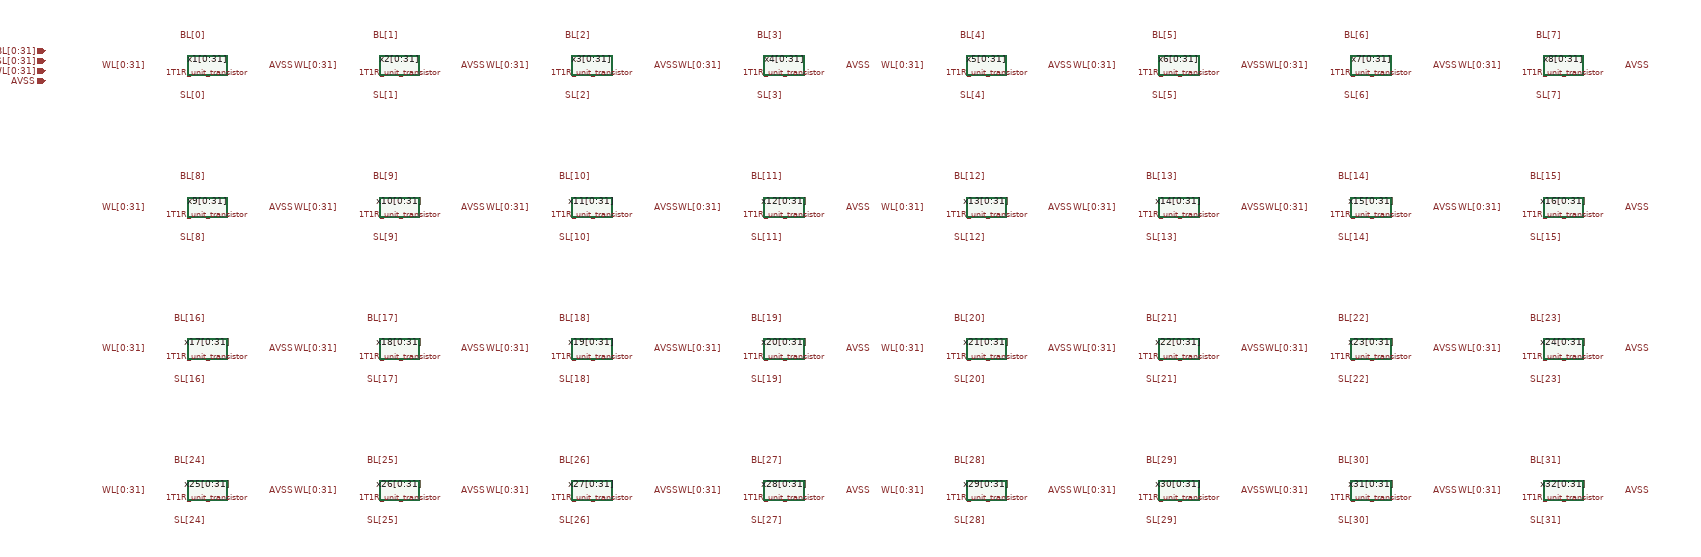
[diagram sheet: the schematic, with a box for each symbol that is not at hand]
v {xschem version=3.1.0 file_version=1.2
}
G {}
K {}
V {}
S {}
E {}
C {devices/iopin.sym} 0 -30 0 0 {name=p1 lab=BL[0:31]}
C {devices/iopin.sym} 0 -10 0 0 {name=p2 lab=SL[0:31]}
C {devices/ipin.sym} 0 10 0 0 {name=p3 lab=WL[0:31]}
C {devices/ipin.sym} 0 30 0 0 {name=p4 lab=AVSS}
C {Top_Level_Array/1T1R_unit_transistor.sym} 320 0 0 0 {name=x1[0:31]}
C {devices/lab_pin.sym} 200 0 0 0 {name=p5 sig_type=std_logic lab=WL[0:31]}
C {devices/lab_pin.sym} 440 0 0 1 {name=p6 sig_type=std_logic lab=AVSS}
C {devices/lab_pin.sym} 320 -60 3 1 {name=p7 sig_type=std_logic lab=BL[0]}
C {devices/lab_pin.sym} 320 60 1 1 {name=p8 sig_type=std_logic lab=SL[0]}
C {Top_Level_Array/1T1R_unit_transistor.sym} 700 0 0 0 {name=x2[0:31]}
C {devices/lab_pin.sym} 580 0 0 0 {name=p9 sig_type=std_logic lab=WL[0:31]}
C {devices/lab_pin.sym} 820 0 0 1 {name=p10 sig_type=std_logic lab=AVSS}
C {devices/lab_pin.sym} 700 -60 3 1 {name=p11 sig_type=std_logic lab=BL[1]}
C {devices/lab_pin.sym} 700 60 1 1 {name=p12 sig_type=std_logic lab=SL[1]}
C {Top_Level_Array/1T1R_unit_transistor.sym} 1080 0 0 0 {name=x3[0:31]}
C {devices/lab_pin.sym} 960 0 0 0 {name=p13 sig_type=std_logic lab=WL[0:31]}
C {devices/lab_pin.sym} 1200 0 0 1 {name=p14 sig_type=std_logic lab=AVSS}
C {devices/lab_pin.sym} 1080 -60 3 1 {name=p15 sig_type=std_logic lab=BL[2]}
C {devices/lab_pin.sym} 1080 60 1 1 {name=p16 sig_type=std_logic lab=SL[2]}
C {Top_Level_Array/1T1R_unit_transistor.sym} 1460 0 0 0 {name=x4[0:31]}
C {devices/lab_pin.sym} 1340 0 0 0 {name=p17 sig_type=std_logic lab=WL[0:31]}
C {devices/lab_pin.sym} 1580 0 0 1 {name=p18 sig_type=std_logic lab=AVSS}
C {devices/lab_pin.sym} 1460 -60 3 1 {name=p19 sig_type=std_logic lab=BL[3]}
C {devices/lab_pin.sym} 1460 60 1 1 {name=p20 sig_type=std_logic lab=SL[3]}
C {Top_Level_Array/1T1R_unit_transistor.sym} 1860 0 0 0 {name=x5[0:31]}
C {devices/lab_pin.sym} 1740 0 0 0 {name=p21 sig_type=std_logic lab=WL[0:31]}
C {devices/lab_pin.sym} 1980 0 0 1 {name=p22 sig_type=std_logic lab=AVSS}
C {devices/lab_pin.sym} 1860 -60 3 1 {name=p23 sig_type=std_logic lab=BL[4]}
C {devices/lab_pin.sym} 1860 60 1 1 {name=p24 sig_type=std_logic lab=SL[4]}
C {Top_Level_Array/1T1R_unit_transistor.sym} 2240 0 0 0 {name=x6[0:31]}
C {devices/lab_pin.sym} 2120 0 0 0 {name=p25 sig_type=std_logic lab=WL[0:31]}
C {devices/lab_pin.sym} 2360 0 0 1 {name=p26 sig_type=std_logic lab=AVSS}
C {devices/lab_pin.sym} 2240 -60 3 1 {name=p27 sig_type=std_logic lab=BL[5]}
C {devices/lab_pin.sym} 2240 60 1 1 {name=p28 sig_type=std_logic lab=SL[5]}
C {Top_Level_Array/1T1R_unit_transistor.sym} 2620 0 0 0 {name=x7[0:31]}
C {devices/lab_pin.sym} 2500 0 0 0 {name=p29 sig_type=std_logic lab=WL[0:31]}
C {devices/lab_pin.sym} 2740 0 0 1 {name=p30 sig_type=std_logic lab=AVSS}
C {devices/lab_pin.sym} 2620 -60 3 1 {name=p31 sig_type=std_logic lab=BL[6]}
C {devices/lab_pin.sym} 2620 60 1 1 {name=p32 sig_type=std_logic lab=SL[6]}
C {Top_Level_Array/1T1R_unit_transistor.sym} 3000 0 0 0 {name=x8[0:31]}
C {devices/lab_pin.sym} 2880 0 0 0 {name=p33 sig_type=std_logic lab=WL[0:31]}
C {devices/lab_pin.sym} 3120 0 0 1 {name=p34 sig_type=std_logic lab=AVSS}
C {devices/lab_pin.sym} 3000 -60 3 1 {name=p35 sig_type=std_logic lab=BL[7]}
C {devices/lab_pin.sym} 3000 60 1 1 {name=p36 sig_type=std_logic lab=SL[7]}
C {Top_Level_Array/1T1R_unit_transistor.sym} 320 280 0 0 {name=x9[0:31]}
C {devices/lab_pin.sym} 200 280 0 0 {name=p37 sig_type=std_logic lab=WL[0:31]}
C {devices/lab_pin.sym} 440 280 0 1 {name=p38 sig_type=std_logic lab=AVSS}
C {devices/lab_pin.sym} 320 220 3 1 {name=p39 sig_type=std_logic lab=BL[8]}
C {devices/lab_pin.sym} 320 340 1 1 {name=p40 sig_type=std_logic lab=SL[8]}
C {Top_Level_Array/1T1R_unit_transistor.sym} 700 280 0 0 {name=x10[0:31]}
C {devices/lab_pin.sym} 580 280 0 0 {name=p41 sig_type=std_logic lab=WL[0:31]}
C {devices/lab_pin.sym} 820 280 0 1 {name=p42 sig_type=std_logic lab=AVSS}
C {devices/lab_pin.sym} 700 220 3 1 {name=p43 sig_type=std_logic lab=BL[9]}
C {devices/lab_pin.sym} 700 340 1 1 {name=p44 sig_type=std_logic lab=SL[9]}
C {Top_Level_Array/1T1R_unit_transistor.sym} 1080 280 0 0 {name=x11[0:31]}
C {devices/lab_pin.sym} 960 280 0 0 {name=p45 sig_type=std_logic lab=WL[0:31]}
C {devices/lab_pin.sym} 1200 280 0 1 {name=p46 sig_type=std_logic lab=AVSS}
C {devices/lab_pin.sym} 1080 220 3 1 {name=p47 sig_type=std_logic lab=BL[10]}
C {devices/lab_pin.sym} 1080 340 1 1 {name=p48 sig_type=std_logic lab=SL[10]}
C {Top_Level_Array/1T1R_unit_transistor.sym} 1460 280 0 0 {name=x12[0:31]}
C {devices/lab_pin.sym} 1340 280 0 0 {name=p49 sig_type=std_logic lab=WL[0:31]}
C {devices/lab_pin.sym} 1580 280 0 1 {name=p50 sig_type=std_logic lab=AVSS}
C {devices/lab_pin.sym} 1460 220 3 1 {name=p51 sig_type=std_logic lab=BL[11]}
C {devices/lab_pin.sym} 1460 340 1 1 {name=p52 sig_type=std_logic lab=SL[11]}
C {Top_Level_Array/1T1R_unit_transistor.sym} 1860 280 0 0 {name=x13[0:31]}
C {devices/lab_pin.sym} 1740 280 0 0 {name=p53 sig_type=std_logic lab=WL[0:31]}
C {devices/lab_pin.sym} 1980 280 0 1 {name=p54 sig_type=std_logic lab=AVSS}
C {devices/lab_pin.sym} 1860 220 3 1 {name=p55 sig_type=std_logic lab=BL[12]}
C {devices/lab_pin.sym} 1860 340 1 1 {name=p56 sig_type=std_logic lab=SL[12]}
C {Top_Level_Array/1T1R_unit_transistor.sym} 2240 280 0 0 {name=x14[0:31]}
C {devices/lab_pin.sym} 2120 280 0 0 {name=p57 sig_type=std_logic lab=WL[0:31]}
C {devices/lab_pin.sym} 2360 280 0 1 {name=p58 sig_type=std_logic lab=AVSS}
C {devices/lab_pin.sym} 2240 220 3 1 {name=p59 sig_type=std_logic lab=BL[13]}
C {devices/lab_pin.sym} 2240 340 1 1 {name=p60 sig_type=std_logic lab=SL[13]}
C {Top_Level_Array/1T1R_unit_transistor.sym} 2620 280 0 0 {name=x15[0:31]}
C {devices/lab_pin.sym} 2500 280 0 0 {name=p61 sig_type=std_logic lab=WL[0:31]}
C {devices/lab_pin.sym} 2740 280 0 1 {name=p62 sig_type=std_logic lab=AVSS}
C {devices/lab_pin.sym} 2620 220 3 1 {name=p63 sig_type=std_logic lab=BL[14]}
C {devices/lab_pin.sym} 2620 340 1 1 {name=p64 sig_type=std_logic lab=SL[14]}
C {Top_Level_Array/1T1R_unit_transistor.sym} 3000 280 0 0 {name=x16[0:31]}
C {devices/lab_pin.sym} 2880 280 0 0 {name=p65 sig_type=std_logic lab=WL[0:31]}
C {devices/lab_pin.sym} 3120 280 0 1 {name=p66 sig_type=std_logic lab=AVSS}
C {devices/lab_pin.sym} 3000 220 3 1 {name=p67 sig_type=std_logic lab=BL[15]}
C {devices/lab_pin.sym} 3000 340 1 1 {name=p68 sig_type=std_logic lab=SL[15]}
C {Top_Level_Array/1T1R_unit_transistor.sym} 320 560 0 0 {name=x17[0:31]}
C {devices/lab_pin.sym} 200 560 0 0 {name=p69 sig_type=std_logic lab=WL[0:31]}
C {devices/lab_pin.sym} 440 560 0 1 {name=p70 sig_type=std_logic lab=AVSS}
C {devices/lab_pin.sym} 320 500 3 1 {name=p71 sig_type=std_logic lab=BL[16]}
C {devices/lab_pin.sym} 320 620 1 1 {name=p72 sig_type=std_logic lab=SL[16]}
C {Top_Level_Array/1T1R_unit_transistor.sym} 700 560 0 0 {name=x18[0:31]}
C {devices/lab_pin.sym} 580 560 0 0 {name=p73 sig_type=std_logic lab=WL[0:31]}
C {devices/lab_pin.sym} 820 560 0 1 {name=p74 sig_type=std_logic lab=AVSS}
C {devices/lab_pin.sym} 700 500 3 1 {name=p75 sig_type=std_logic lab=BL[17]}
C {devices/lab_pin.sym} 700 620 1 1 {name=p76 sig_type=std_logic lab=SL[17]}
C {Top_Level_Array/1T1R_unit_transistor.sym} 1080 560 0 0 {name=x19[0:31]}
C {devices/lab_pin.sym} 960 560 0 0 {name=p77 sig_type=std_logic lab=WL[0:31]}
C {devices/lab_pin.sym} 1200 560 0 1 {name=p78 sig_type=std_logic lab=AVSS}
C {devices/lab_pin.sym} 1080 500 3 1 {name=p79 sig_type=std_logic lab=BL[18]}
C {devices/lab_pin.sym} 1080 620 1 1 {name=p80 sig_type=std_logic lab=SL[18]}
C {Top_Level_Array/1T1R_unit_transistor.sym} 1460 560 0 0 {name=x20[0:31]}
C {devices/lab_pin.sym} 1340 560 0 0 {name=p81 sig_type=std_logic lab=WL[0:31]}
C {devices/lab_pin.sym} 1580 560 0 1 {name=p82 sig_type=std_logic lab=AVSS}
C {devices/lab_pin.sym} 1460 500 3 1 {name=p83 sig_type=std_logic lab=BL[19]}
C {devices/lab_pin.sym} 1460 620 1 1 {name=p84 sig_type=std_logic lab=SL[19]}
C {Top_Level_Array/1T1R_unit_transistor.sym} 1860 560 0 0 {name=x21[0:31]}
C {devices/lab_pin.sym} 1740 560 0 0 {name=p85 sig_type=std_logic lab=WL[0:31]}
C {devices/lab_pin.sym} 1980 560 0 1 {name=p86 sig_type=std_logic lab=AVSS}
C {devices/lab_pin.sym} 1860 500 3 1 {name=p87 sig_type=std_logic lab=BL[20]}
C {devices/lab_pin.sym} 1860 620 1 1 {name=p88 sig_type=std_logic lab=SL[20]}
C {Top_Level_Array/1T1R_unit_transistor.sym} 2240 560 0 0 {name=x22[0:31]}
C {devices/lab_pin.sym} 2120 560 0 0 {name=p89 sig_type=std_logic lab=WL[0:31]}
C {devices/lab_pin.sym} 2360 560 0 1 {name=p90 sig_type=std_logic lab=AVSS}
C {devices/lab_pin.sym} 2240 500 3 1 {name=p91 sig_type=std_logic lab=BL[21]}
C {devices/lab_pin.sym} 2240 620 1 1 {name=p92 sig_type=std_logic lab=SL[21]}
C {Top_Level_Array/1T1R_unit_transistor.sym} 2620 560 0 0 {name=x23[0:31]}
C {devices/lab_pin.sym} 2500 560 0 0 {name=p93 sig_type=std_logic lab=WL[0:31]}
C {devices/lab_pin.sym} 2740 560 0 1 {name=p94 sig_type=std_logic lab=AVSS}
C {devices/lab_pin.sym} 2620 500 3 1 {name=p95 sig_type=std_logic lab=BL[22]}
C {devices/lab_pin.sym} 2620 620 1 1 {name=p96 sig_type=std_logic lab=SL[22]}
C {Top_Level_Array/1T1R_unit_transistor.sym} 3000 560 0 0 {name=x24[0:31]}
C {devices/lab_pin.sym} 200 840 0 0 {name=p97 sig_type=std_logic lab=WL[0:31]}
C {devices/lab_pin.sym} 440 840 0 1 {name=p98 sig_type=std_logic lab=AVSS}
C {devices/lab_pin.sym} 320 780 3 1 {name=p99 sig_type=std_logic lab=BL[24]}
C {devices/lab_pin.sym} 320 900 1 1 {name=p100 sig_type=std_logic lab=SL[24]}
C {Top_Level_Array/1T1R_unit_transistor.sym} 320 840 0 0 {name=x25[0:31]}
C {devices/lab_pin.sym} 580 840 0 0 {name=p101 sig_type=std_logic lab=WL[0:31]}
C {devices/lab_pin.sym} 820 840 0 1 {name=p102 sig_type=std_logic lab=AVSS}
C {devices/lab_pin.sym} 700 780 3 1 {name=p103 sig_type=std_logic lab=BL[25]}
C {devices/lab_pin.sym} 700 900 1 1 {name=p104 sig_type=std_logic lab=SL[25]}
C {Top_Level_Array/1T1R_unit_transistor.sym} 700 840 0 0 {name=x26[0:31]}
C {devices/lab_pin.sym} 960 840 0 0 {name=p105 sig_type=std_logic lab=WL[0:31]}
C {devices/lab_pin.sym} 1200 840 0 1 {name=p106 sig_type=std_logic lab=AVSS}
C {devices/lab_pin.sym} 1080 780 3 1 {name=p107 sig_type=std_logic lab=BL[26]}
C {devices/lab_pin.sym} 1080 900 1 1 {name=p108 sig_type=std_logic lab=SL[26]}
C {Top_Level_Array/1T1R_unit_transistor.sym} 1080 840 0 0 {name=x27[0:31]}
C {devices/lab_pin.sym} 1340 840 0 0 {name=p109 sig_type=std_logic lab=WL[0:31]}
C {devices/lab_pin.sym} 1580 840 0 1 {name=p110 sig_type=std_logic lab=AVSS}
C {devices/lab_pin.sym} 1460 780 3 1 {name=p111 sig_type=std_logic lab=BL[27]}
C {devices/lab_pin.sym} 1460 900 1 1 {name=p112 sig_type=std_logic lab=SL[27]}
C {Top_Level_Array/1T1R_unit_transistor.sym} 1460 840 0 0 {name=x28[0:31]}
C {devices/lab_pin.sym} 1740 840 0 0 {name=p113 sig_type=std_logic lab=WL[0:31]}
C {devices/lab_pin.sym} 1980 840 0 1 {name=p114 sig_type=std_logic lab=AVSS}
C {devices/lab_pin.sym} 1860 780 3 1 {name=p115 sig_type=std_logic lab=BL[28]}
C {devices/lab_pin.sym} 1860 900 1 1 {name=p116 sig_type=std_logic lab=SL[28]}
C {Top_Level_Array/1T1R_unit_transistor.sym} 1860 840 0 0 {name=x29[0:31]}
C {devices/lab_pin.sym} 2120 840 0 0 {name=p117 sig_type=std_logic lab=WL[0:31]}
C {devices/lab_pin.sym} 2360 840 0 1 {name=p118 sig_type=std_logic lab=AVSS}
C {devices/lab_pin.sym} 2240 780 3 1 {name=p119 sig_type=std_logic lab=BL[29]}
C {devices/lab_pin.sym} 2240 900 1 1 {name=p120 sig_type=std_logic lab=SL[29]}
C {Top_Level_Array/1T1R_unit_transistor.sym} 2240 840 0 0 {name=x30[0:31]}
C {devices/lab_pin.sym} 2880 560 0 0 {name=p125 sig_type=std_logic lab=WL[0:31]}
C {devices/lab_pin.sym} 3120 560 0 1 {name=p126 sig_type=std_logic lab=AVSS}
C {devices/lab_pin.sym} 3000 500 3 1 {name=p127 sig_type=std_logic lab=BL[23]}
C {devices/lab_pin.sym} 3000 620 1 1 {name=p128 sig_type=std_logic lab=SL[23]}
C {devices/lab_pin.sym} 2500 840 0 0 {name=p121 sig_type=std_logic lab=WL[0:31]}
C {devices/lab_pin.sym} 2740 840 0 1 {name=p122 sig_type=std_logic lab=AVSS}
C {devices/lab_pin.sym} 2620 780 3 1 {name=p123 sig_type=std_logic lab=BL[30]}
C {devices/lab_pin.sym} 2620 900 1 1 {name=p124 sig_type=std_logic lab=SL[30]}
C {Top_Level_Array/1T1R_unit_transistor.sym} 2620 840 0 0 {name=x31[0:31]}
C {devices/lab_pin.sym} 2880 840 0 0 {name=p129 sig_type=std_logic lab=WL[0:31]}
C {devices/lab_pin.sym} 3120 840 0 1 {name=p130 sig_type=std_logic lab=AVSS}
C {devices/lab_pin.sym} 3000 780 3 1 {name=p131 sig_type=std_logic lab=BL[31]}
C {devices/lab_pin.sym} 3000 900 1 1 {name=p132 sig_type=std_logic lab=SL[31]}
C {Top_Level_Array/1T1R_unit_transistor.sym} 3000 840 0 0 {name=x32[0:31]}
